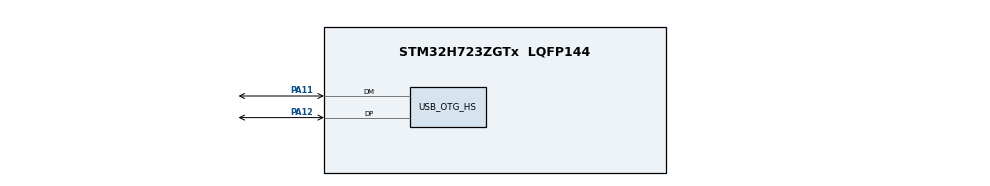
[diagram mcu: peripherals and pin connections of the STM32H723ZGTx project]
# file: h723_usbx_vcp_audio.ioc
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Mcu.Family=STM32H7
Mcu.Name=STM32H723ZGTx
Mcu.Package=LQFP144
NVIC.OTG_HS_IRQn=true\:0\:0\:false\:false\:true\:false\:true\:true\:true
NVIC.PriorityGroup=NVIC_PRIORITYGROUP_4
NVIC.TIM23_IRQn=true\:15\:0\:false\:false\:true\:false\:false\:true\:true
NVIC.TimeBase=TIM23_IRQn
NVIC.TimeBaseIP=TIM23
PA11.Mode=Device_Only_FS
PA11.Signal=USB_OTG_HS_DM
PA12.Mode=Device_Only_FS
PA12.Signal=USB_OTG_HS_DP
ProjectManager.HeapSize=0x200
ProjectManager.StackSize=0x400
ProjectManager.TargetToolchain=STM32CubeIDE
RCC.ADCFreq_Value=16125000
RCC.APB1Freq_Value=137500000
RCC.APB2Freq_Value=137500000
RCC.APB3Freq_Value=137500000
RCC.APB4Freq_Value=137500000
RCC.CortexFreq_Value=550000000
RCC.D1PPRE=RCC_APB3_DIV2
RCC.D2PPRE1=RCC_APB1_DIV2
RCC.D2PPRE2=RCC_APB2_DIV2
RCC.D3PPRE=RCC_APB4_DIV2
RCC.DIVM1=4
RCC.DIVN1=275
RCC.DIVP1=1
RCC.HCLKFreq_Value=275000000
RCC.HPRE=RCC_HCLK_DIV2
RCC.HSIDiv=RCC_PLLSAIDIVR_8
RCC.SYSCLKFreq_VALUE=550000000
RCC.SYSCLKSource=RCC_SYSCLKSOURCE_PLLCLK
RCC.USBCLockSelection=RCC_USBCLKSOURCE_HSI48
RCC.USBFreq_Value=48000000
STMicroelectronics.X-CUBE-AZRTOS-H7.3.1.0.REG_UX_DEVICE_CORE=true
STMicroelectronics.X-CUBE-AZRTOS-H7.3.1.0.TX_APP_GENERATE_INIT_CODE=false
STMicroelectronics.X-CUBE-AZRTOS-H7.3.1.0.TX_APP_MEM_POOL_SIZE=1024*20
STMicroelectronics.X-CUBE-AZRTOS-H7.3.1.0.ThreadXCcRTOSJjThreadXJjCore=true
STMicroelectronics.X-CUBE-AZRTOS-H7.3.1.0.USBD_CDCACM_EPIN_ADDR=2
STMicroelectronics.X-CUBE-AZRTOS-H7.3.1.0.USBD_CDCACM_EPOUT_ADDR=2
STMicroelectronics.X-CUBE-AZRTOS-H7.3.1.0.USBXCcUSBJjUSBXJjCoreSystem=true
STMicroelectronics.X-CUBE-AZRTOS-H7.3.1.0.USBXCcUSBJjUSBXJjUXOoDeviceOoClassOoAUDIO=true
STMicroelectronics.X-CUBE-AZRTOS-H7.3.1.0.USBXCcUSBJjUSBXJjUXOoDeviceOoClassOoCDCOoACM=true
STMicroelectronics.X-CUBE-AZRTOS-H7.3.1.0.USBXCcUSBJjUSBXJjUXOoDeviceOoControllers=true
STMicroelectronics.X-CUBE-AZRTOS-H7.3.1.0.USBXCcUSBJjUSBXJjUXOoDeviceOoCoreStack=true
STMicroelectronics.X-CUBE-AZRTOS-H7.3.1.0.USBX_DEVICE_SYS_SIZE=1024*50
STMicroelectronics.X-CUBE-AZRTOS-H7.3.1.0.UX_DEVICE_APP_MEM_POOL_SIZE=1024*20
STMicroelectronics.X-CUBE-AZRTOS-H7.3.1.0.UX_MAX_SLAVE_CLASS_DRIVER=2
STMicroelectronics.X-CUBE-AZRTOS-H7.3.1.0_IsAnAzureRtosMw=true
USB_OTG_HS.VirtualMode-Device_Only_FS=Device_Only_FS
VP_RCC_USB.Mode=USB_HS
VP_STMicroelectronics.X-CUBE-AZRTOS-H7_VS_RTOSJjThreadX_6.2.0_3.1.0.Mode=RTOSJjThreadX
VP_STMicroelectronics.X-CUBE-AZRTOS-H7_VS_USBJjUSBX_6.2.0_3.1.0.Mode=USBJjUSBX
VP_SYS_VS_tim23.Mode=TIM23
board=custom

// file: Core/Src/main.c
/* USER CODE BEGIN Header */
/**
  ******************************************************************************
  * @file           : main.c
  * @brief          : Main program body
  ******************************************************************************
  * @attention
  *
  * Copyright (c) 2023 STMicroelectronics.
  * All rights reserved.
  *
  * This software is licensed under terms that can be found in the LICENSE file
  * in the root directory of this software component.
  * If no LICENSE file comes with this software, it is provided AS-IS.
  *
  ******************************************************************************
  */
/* USER CODE END Header */
#include "app_threadx.h"
#include "main.h"

PCD_HandleTypeDef hpcd_USB_OTG_HS;

void SystemClock_Config(void);
static void MPU_Initialize(void);
static void MPU_Config(void);
static void MX_GPIO_Init(void);
static void MX_USB_OTG_HS_PCD_Init(void);

int main(void)
{

  /* MCU Configuration--------------------------------------------------------*/

  /* Reset of all peripherals, Initializes the Flash interface and the Systick. */
  HAL_Init();

  /* MPU Configuration--------------------------------------------------------*/
  MPU_Config();

  /* Configure the system clock */
  SystemClock_Config();

  /* USER CODE BEGIN SysInit */
  {
    GPIO_InitTypeDef   GPIO_InitStructure;
    __HAL_RCC_GPIOG_CLK_ENABLE();
    GPIO_InitStructure.Pin = GPIO_PIN_0|GPIO_PIN_1;
    GPIO_InitStructure.Mode = GPIO_MODE_OUTPUT_PP;
    GPIO_InitStructure.Pull = GPIO_NOPULL;
    GPIO_InitStructure.Speed = GPIO_SPEED_FREQ_HIGH;
    HAL_GPIO_Init(GPIOG, &GPIO_InitStructure);
  }
  /* USER CODE END SysInit */

  /* Initialize all configured peripherals */
  MX_GPIO_Init();
  MX_USB_OTG_HS_PCD_Init();

  MX_ThreadX_Init();

  /* We should never get here as control is now taken by the scheduler */
  /* Infinite loop */
  while (1)
  {

  }
}

void SystemClock_Config(void)
{
  RCC_OscInitTypeDef RCC_OscInitStruct = {0};
  RCC_ClkInitTypeDef RCC_ClkInitStruct = {0};
  RCC_CRSInitTypeDef RCC_CRSInitStruct = {0};

  /** Supply configuration update enable
  */
  HAL_PWREx_ConfigSupply(PWR_LDO_SUPPLY);

  /** Configure the main internal regulator output voltage
  */
  __HAL_PWR_VOLTAGESCALING_CONFIG(PWR_REGULATOR_VOLTAGE_SCALE0);

  while(!__HAL_PWR_GET_FLAG(PWR_FLAG_VOSRDY)) {}

  /** Initializes the RCC Oscillators according to the specified parameters
  * in the RCC_OscInitTypeDef structure.
  */
  RCC_OscInitStruct.OscillatorType = RCC_OSCILLATORTYPE_HSI48|RCC_OSCILLATORTYPE_HSI;
  RCC_OscInitStruct.HSIState = RCC_HSI_DIV8;
  RCC_OscInitStruct.HSICalibrationValue = 64;
  RCC_OscInitStruct.HSI48State = RCC_HSI48_ON;
  RCC_OscInitStruct.PLL.PLLState = RCC_PLL_ON;
  RCC_OscInitStruct.PLL.PLLSource = RCC_PLLSOURCE_HSI;
  RCC_OscInitStruct.PLL.PLLM = 4;
  RCC_OscInitStruct.PLL.PLLN = 275;
  RCC_OscInitStruct.PLL.PLLP = 1;
  RCC_OscInitStruct.PLL.PLLQ = 2;
  RCC_OscInitStruct.PLL.PLLR = 2;
  RCC_OscInitStruct.PLL.PLLRGE = RCC_PLL1VCIRANGE_1;
  RCC_OscInitStruct.PLL.PLLVCOSEL = RCC_PLL1VCOWIDE;
  RCC_OscInitStruct.PLL.PLLFRACN = 0;
  if (HAL_RCC_OscConfig(&RCC_OscInitStruct) != HAL_OK)
  {
    Error_Handler();
  }

  /** Initializes the CPU, AHB and APB buses clocks
  */
  RCC_ClkInitStruct.ClockType = RCC_CLOCKTYPE_HCLK|RCC_CLOCKTYPE_SYSCLK
                              |RCC_CLOCKTYPE_PCLK1|RCC_CLOCKTYPE_PCLK2
                              |RCC_CLOCKTYPE_D3PCLK1|RCC_CLOCKTYPE_D1PCLK1;
  RCC_ClkInitStruct.SYSCLKSource = RCC_SYSCLKSOURCE_PLLCLK;
  RCC_ClkInitStruct.SYSCLKDivider = RCC_SYSCLK_DIV1;
  RCC_ClkInitStruct.AHBCLKDivider = RCC_HCLK_DIV2;
  RCC_ClkInitStruct.APB3CLKDivider = RCC_APB3_DIV2;
  RCC_ClkInitStruct.APB1CLKDivider = RCC_APB1_DIV2;
  RCC_ClkInitStruct.APB2CLKDivider = RCC_APB2_DIV2;
  RCC_ClkInitStruct.APB4CLKDivider = RCC_APB4_DIV2;

  if (HAL_RCC_ClockConfig(&RCC_ClkInitStruct, FLASH_LATENCY_3) != HAL_OK)
  {
    Error_Handler();
  }

  /** Enable the SYSCFG APB clock
  */
  __HAL_RCC_CRS_CLK_ENABLE();

  /** Configures CRS
  */
  RCC_CRSInitStruct.Prescaler = RCC_CRS_SYNC_DIV1;
  RCC_CRSInitStruct.Source = RCC_CRS_SYNC_SOURCE_USB2;
  RCC_CRSInitStruct.Polarity = RCC_CRS_SYNC_POLARITY_RISING;
  RCC_CRSInitStruct.ReloadValue = __HAL_RCC_CRS_RELOADVALUE_CALCULATE(48000000,1000);
  RCC_CRSInitStruct.ErrorLimitValue = 34;
  RCC_CRSInitStruct.HSI48CalibrationValue = 32;

  HAL_RCCEx_CRSConfig(&RCC_CRSInitStruct);
}

static void MX_USB_OTG_HS_PCD_Init(void)
{

  hpcd_USB_OTG_HS.Instance = USB_OTG_HS;
  hpcd_USB_OTG_HS.Init.dev_endpoints = 9;
  hpcd_USB_OTG_HS.Init.speed = PCD_SPEED_FULL;
  hpcd_USB_OTG_HS.Init.dma_enable = DISABLE;
  hpcd_USB_OTG_HS.Init.phy_itface = USB_OTG_EMBEDDED_PHY;
  hpcd_USB_OTG_HS.Init.Sof_enable = ENABLE;
  hpcd_USB_OTG_HS.Init.low_power_enable = DISABLE;
  hpcd_USB_OTG_HS.Init.lpm_enable = DISABLE;
  hpcd_USB_OTG_HS.Init.vbus_sensing_enable = DISABLE;
  hpcd_USB_OTG_HS.Init.use_dedicated_ep1 = DISABLE;
  hpcd_USB_OTG_HS.Init.use_external_vbus = DISABLE;
  if (HAL_PCD_Init(&hpcd_USB_OTG_HS) != HAL_OK)
  {
    Error_Handler();
  }

}

static void MX_GPIO_Init(void)
{

  /* GPIO Ports Clock Enable */
  __HAL_RCC_GPIOA_CLK_ENABLE();

}

/* MPU Configuration */

void MPU_Config(void)
{
  MPU_Region_InitTypeDef MPU_InitStruct = {0};

  /* Disables the MPU */
  HAL_MPU_Disable();

  /** Initializes and configures the Region and the memory to be protected
  */
  MPU_InitStruct.Enable = MPU_REGION_ENABLE;
  MPU_InitStruct.Number = MPU_REGION_NUMBER0;
  MPU_InitStruct.BaseAddress = 0x0;
  MPU_InitStruct.Size = MPU_REGION_SIZE_4GB;
  MPU_InitStruct.SubRegionDisable = 0x87;
  MPU_InitStruct.TypeExtField = MPU_TEX_LEVEL0;
  MPU_InitStruct.AccessPermission = MPU_REGION_NO_ACCESS;
  MPU_InitStruct.DisableExec = MPU_INSTRUCTION_ACCESS_DISABLE;
  MPU_InitStruct.IsShareable = MPU_ACCESS_SHAREABLE;
  MPU_InitStruct.IsCacheable = MPU_ACCESS_NOT_CACHEABLE;
  MPU_InitStruct.IsBufferable = MPU_ACCESS_NOT_BUFFERABLE;

  HAL_MPU_ConfigRegion(&MPU_InitStruct);
  /* Enables the MPU */
  HAL_MPU_Enable(MPU_PRIVILEGED_DEFAULT);

}

void HAL_TIM_PeriodElapsedCallback(TIM_HandleTypeDef *htim)
{
  if (htim->Instance == TIM23) {
    HAL_IncTick();
  }
}

void Error_Handler(void)
{
  __disable_irq();
  while (1)
  {
  }
}
